VERSION 5.7 ;
BUSBITCHARS "[]" ;
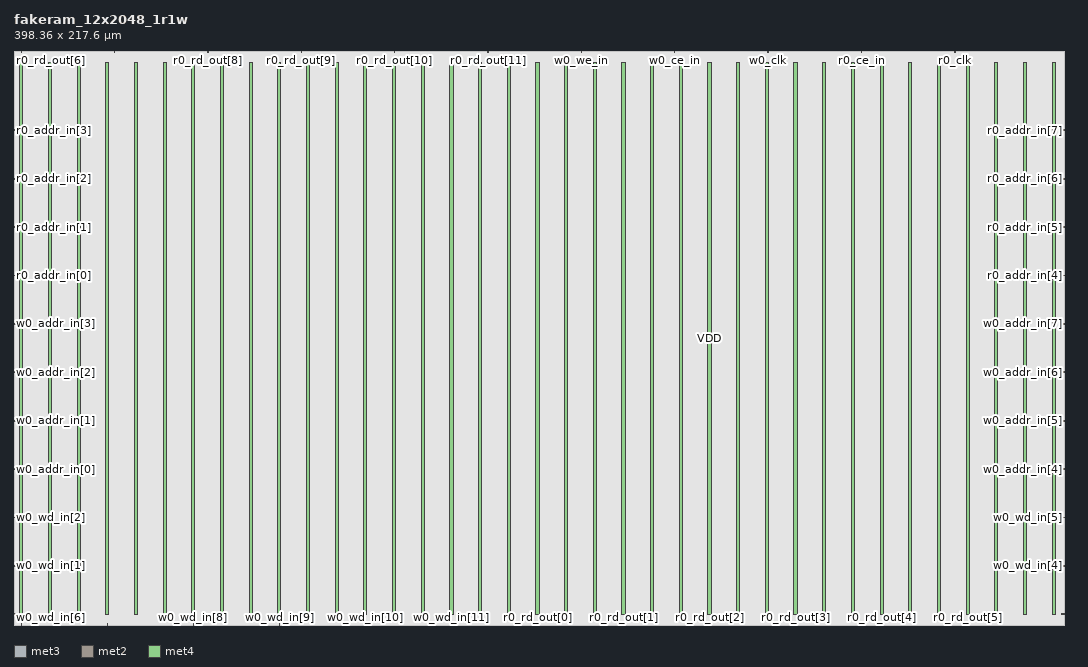
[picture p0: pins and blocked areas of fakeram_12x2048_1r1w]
MACRO fakeram_12x2048_1r1w
  FOREIGN fakeram_12x2048_1r1w 0 0 ;
  SYMMETRY X Y R90 ;
  SIZE 398.360 BY 217.600 ;
  CLASS BLOCK ;
  PIN w0_wd_in[0]
    DIRECTION INPUT ;
    USE SIGNAL ;
    SHAPE ABUTMENT ;
    PORT
      LAYER met3 ;
      RECT 0.000 3.930 0.900 4.230 ;
    END
  END w0_wd_in[0]
  PIN w0_wd_in[1]
    DIRECTION INPUT ;
    USE SIGNAL ;
    SHAPE ABUTMENT ;
    PORT
      LAYER met3 ;
      RECT 0.000 22.290 0.900 22.590 ;
    END
  END w0_wd_in[1]
  PIN w0_wd_in[2]
    DIRECTION INPUT ;
    USE SIGNAL ;
    SHAPE ABUTMENT ;
    PORT
      LAYER met3 ;
      RECT 0.000 40.650 0.900 40.950 ;
    END
  END w0_wd_in[2]
  PIN w0_wd_in[3]
    DIRECTION INPUT ;
    USE SIGNAL ;
    SHAPE ABUTMENT ;
    PORT
      LAYER met3 ;
      RECT 397.460 3.930 398.360 4.230 ;
    END
  END w0_wd_in[3]
  PIN w0_wd_in[4]
    DIRECTION INPUT ;
    USE SIGNAL ;
    SHAPE ABUTMENT ;
    PORT
      LAYER met3 ;
      RECT 397.460 22.290 398.360 22.590 ;
    END
  END w0_wd_in[4]
  PIN w0_wd_in[5]
    DIRECTION INPUT ;
    USE SIGNAL ;
    SHAPE ABUTMENT ;
    PORT
      LAYER met3 ;
      RECT 397.460 40.650 398.360 40.950 ;
    END
  END w0_wd_in[5]
  PIN w0_wd_in[6]
    DIRECTION INPUT ;
    USE SIGNAL ;
    SHAPE ABUTMENT ;
    PORT
      LAYER met2 ;
      RECT 2.690 0.000 2.830 0.420 ;
    END
  END w0_wd_in[6]
  PIN w0_wd_in[7]
    DIRECTION INPUT ;
    USE SIGNAL ;
    SHAPE ABUTMENT ;
    PORT
      LAYER met2 ;
      RECT 35.350 0.000 35.490 0.420 ;
    END
  END w0_wd_in[7]
  PIN w0_wd_in[8]
    DIRECTION INPUT ;
    USE SIGNAL ;
    SHAPE ABUTMENT ;
    PORT
      LAYER met2 ;
      RECT 68.010 0.000 68.150 0.420 ;
    END
  END w0_wd_in[8]
  PIN w0_wd_in[9]
    DIRECTION INPUT ;
    USE SIGNAL ;
    SHAPE ABUTMENT ;
    PORT
      LAYER met2 ;
      RECT 100.670 0.000 100.810 0.420 ;
    END
  END w0_wd_in[9]
  PIN w0_wd_in[10]
    DIRECTION INPUT ;
    USE SIGNAL ;
    SHAPE ABUTMENT ;
    PORT
      LAYER met2 ;
      RECT 133.330 0.000 133.470 0.420 ;
    END
  END w0_wd_in[10]
  PIN w0_wd_in[11]
    DIRECTION INPUT ;
    USE SIGNAL ;
    SHAPE ABUTMENT ;
    PORT
      LAYER met2 ;
      RECT 165.990 0.000 166.130 0.420 ;
    END
  END w0_wd_in[11]
  PIN r0_rd_out[0]
    DIRECTION OUTPUT ;
    USE SIGNAL ;
    SHAPE ABUTMENT ;
    PORT
      LAYER met2 ;
      RECT 198.650 0.000 198.790 0.420 ;
    END
  END r0_rd_out[0]
  PIN r0_rd_out[1]
    DIRECTION OUTPUT ;
    USE SIGNAL ;
    SHAPE ABUTMENT ;
    PORT
      LAYER met2 ;
      RECT 231.310 0.000 231.450 0.420 ;
    END
  END r0_rd_out[1]
  PIN r0_rd_out[2]
    DIRECTION OUTPUT ;
    USE SIGNAL ;
    SHAPE ABUTMENT ;
    PORT
      LAYER met2 ;
      RECT 263.970 0.000 264.110 0.420 ;
    END
  END r0_rd_out[2]
  PIN r0_rd_out[3]
    DIRECTION OUTPUT ;
    USE SIGNAL ;
    SHAPE ABUTMENT ;
    PORT
      LAYER met2 ;
      RECT 296.630 0.000 296.770 0.420 ;
    END
  END r0_rd_out[3]
  PIN r0_rd_out[4]
    DIRECTION OUTPUT ;
    USE SIGNAL ;
    SHAPE ABUTMENT ;
    PORT
      LAYER met2 ;
      RECT 329.290 0.000 329.430 0.420 ;
    END
  END r0_rd_out[4]
  PIN r0_rd_out[5]
    DIRECTION OUTPUT ;
    USE SIGNAL ;
    SHAPE ABUTMENT ;
    PORT
      LAYER met2 ;
      RECT 361.950 0.000 362.090 0.420 ;
    END
  END r0_rd_out[5]
  PIN r0_rd_out[6]
    DIRECTION OUTPUT ;
    USE SIGNAL ;
    SHAPE ABUTMENT ;
    PORT
      LAYER met2 ;
      RECT 2.690 217.180 2.830 217.600 ;
    END
  END r0_rd_out[6]
  PIN r0_rd_out[7]
    DIRECTION OUTPUT ;
    USE SIGNAL ;
    SHAPE ABUTMENT ;
    PORT
      LAYER met2 ;
      RECT 38.110 217.180 38.250 217.600 ;
    END
  END r0_rd_out[7]
  PIN r0_rd_out[8]
    DIRECTION OUTPUT ;
    USE SIGNAL ;
    SHAPE ABUTMENT ;
    PORT
      LAYER met2 ;
      RECT 73.530 217.180 73.670 217.600 ;
    END
  END r0_rd_out[8]
  PIN r0_rd_out[9]
    DIRECTION OUTPUT ;
    USE SIGNAL ;
    SHAPE ABUTMENT ;
    PORT
      LAYER met2 ;
      RECT 108.950 217.180 109.090 217.600 ;
    END
  END r0_rd_out[9]
  PIN r0_rd_out[10]
    DIRECTION OUTPUT ;
    USE SIGNAL ;
    SHAPE ABUTMENT ;
    PORT
      LAYER met2 ;
      RECT 144.370 217.180 144.510 217.600 ;
    END
  END r0_rd_out[10]
  PIN r0_rd_out[11]
    DIRECTION OUTPUT ;
    USE SIGNAL ;
    SHAPE ABUTMENT ;
    PORT
      LAYER met2 ;
      RECT 179.790 217.180 179.930 217.600 ;
    END
  END r0_rd_out[11]
  PIN w0_addr_in[0]
    DIRECTION INPUT ;
    USE SIGNAL ;
    SHAPE ABUTMENT ;
    PORT
      LAYER met3 ;
      RECT 0.000 59.010 0.900 59.310 ;
    END
  END w0_addr_in[0]
  PIN w0_addr_in[1]
    DIRECTION INPUT ;
    USE SIGNAL ;
    SHAPE ABUTMENT ;
    PORT
      LAYER met3 ;
      RECT 0.000 77.370 0.900 77.670 ;
    END
  END w0_addr_in[1]
  PIN w0_addr_in[2]
    DIRECTION INPUT ;
    USE SIGNAL ;
    SHAPE ABUTMENT ;
    PORT
      LAYER met3 ;
      RECT 0.000 95.730 0.900 96.030 ;
    END
  END w0_addr_in[2]
  PIN w0_addr_in[3]
    DIRECTION INPUT ;
    USE SIGNAL ;
    SHAPE ABUTMENT ;
    PORT
      LAYER met3 ;
      RECT 0.000 114.090 0.900 114.390 ;
    END
  END w0_addr_in[3]
  PIN w0_addr_in[4]
    DIRECTION INPUT ;
    USE SIGNAL ;
    SHAPE ABUTMENT ;
    PORT
      LAYER met3 ;
      RECT 397.460 59.010 398.360 59.310 ;
    END
  END w0_addr_in[4]
  PIN w0_addr_in[5]
    DIRECTION INPUT ;
    USE SIGNAL ;
    SHAPE ABUTMENT ;
    PORT
      LAYER met3 ;
      RECT 397.460 77.370 398.360 77.670 ;
    END
  END w0_addr_in[5]
  PIN w0_addr_in[6]
    DIRECTION INPUT ;
    USE SIGNAL ;
    SHAPE ABUTMENT ;
    PORT
      LAYER met3 ;
      RECT 397.460 95.730 398.360 96.030 ;
    END
  END w0_addr_in[6]
  PIN w0_addr_in[7]
    DIRECTION INPUT ;
    USE SIGNAL ;
    SHAPE ABUTMENT ;
    PORT
      LAYER met3 ;
      RECT 397.460 114.090 398.360 114.390 ;
    END
  END w0_addr_in[7]
  PIN r0_addr_in[0]
    DIRECTION INPUT ;
    USE SIGNAL ;
    SHAPE ABUTMENT ;
    PORT
      LAYER met3 ;
      RECT 0.000 132.450 0.900 132.750 ;
    END
  END r0_addr_in[0]
  PIN r0_addr_in[1]
    DIRECTION INPUT ;
    USE SIGNAL ;
    SHAPE ABUTMENT ;
    PORT
      LAYER met3 ;
      RECT 0.000 150.810 0.900 151.110 ;
    END
  END r0_addr_in[1]
  PIN r0_addr_in[2]
    DIRECTION INPUT ;
    USE SIGNAL ;
    SHAPE ABUTMENT ;
    PORT
      LAYER met3 ;
      RECT 0.000 169.170 0.900 169.470 ;
    END
  END r0_addr_in[2]
  PIN r0_addr_in[3]
    DIRECTION INPUT ;
    USE SIGNAL ;
    SHAPE ABUTMENT ;
    PORT
      LAYER met3 ;
      RECT 0.000 187.530 0.900 187.830 ;
    END
  END r0_addr_in[3]
  PIN r0_addr_in[4]
    DIRECTION INPUT ;
    USE SIGNAL ;
    SHAPE ABUTMENT ;
    PORT
      LAYER met3 ;
      RECT 397.460 132.450 398.360 132.750 ;
    END
  END r0_addr_in[4]
  PIN r0_addr_in[5]
    DIRECTION INPUT ;
    USE SIGNAL ;
    SHAPE ABUTMENT ;
    PORT
      LAYER met3 ;
      RECT 397.460 150.810 398.360 151.110 ;
    END
  END r0_addr_in[5]
  PIN r0_addr_in[6]
    DIRECTION INPUT ;
    USE SIGNAL ;
    SHAPE ABUTMENT ;
    PORT
      LAYER met3 ;
      RECT 397.460 169.170 398.360 169.470 ;
    END
  END r0_addr_in[6]
  PIN r0_addr_in[7]
    DIRECTION INPUT ;
    USE SIGNAL ;
    SHAPE ABUTMENT ;
    PORT
      LAYER met3 ;
      RECT 397.460 187.530 398.360 187.830 ;
    END
  END r0_addr_in[7]
  PIN w0_we_in
    DIRECTION INPUT ;
    USE SIGNAL ;
    SHAPE ABUTMENT ;
    PORT
      LAYER met2 ;
      RECT 215.210 217.180 215.350 217.600 ;
    END
  END w0_we_in
  PIN w0_ce_in
    DIRECTION INPUT ;
    USE SIGNAL ;
    SHAPE ABUTMENT ;
    PORT
      LAYER met2 ;
      RECT 250.630 217.180 250.770 217.600 ;
    END
  END w0_ce_in
  PIN w0_clk
    DIRECTION INPUT ;
    USE SIGNAL ;
    SHAPE ABUTMENT ;
    PORT
      LAYER met2 ;
      RECT 286.050 217.180 286.190 217.600 ;
    END
  END w0_clk
  PIN r0_ce_in
    DIRECTION INPUT ;
    USE SIGNAL ;
    SHAPE ABUTMENT ;
    PORT
      LAYER met2 ;
      RECT 321.470 217.180 321.610 217.600 ;
    END
  END r0_ce_in
  PIN r0_clk
    DIRECTION INPUT ;
    USE SIGNAL ;
    SHAPE ABUTMENT ;
    PORT
      LAYER met2 ;
      RECT 356.890 217.180 357.030 217.600 ;
    END
  END r0_clk
  PIN VSS
    DIRECTION INOUT ;
    USE GROUND ;
    PORT
      LAYER met4 ;
      RECT 2.160 4.080 3.360 213.520 ;
      RECT 13.040 4.080 14.240 213.520 ;
      RECT 23.920 4.080 25.120 213.520 ;
      RECT 34.800 4.080 36.000 213.520 ;
      RECT 45.680 4.080 46.880 213.520 ;
      RECT 56.560 4.080 57.760 213.520 ;
      RECT 67.440 4.080 68.640 213.520 ;
      RECT 78.320 4.080 79.520 213.520 ;
      RECT 89.200 4.080 90.400 213.520 ;
      RECT 100.080 4.080 101.280 213.520 ;
      RECT 110.960 4.080 112.160 213.520 ;
      RECT 121.840 4.080 123.040 213.520 ;
      RECT 132.720 4.080 133.920 213.520 ;
      RECT 143.600 4.080 144.800 213.520 ;
      RECT 154.480 4.080 155.680 213.520 ;
      RECT 165.360 4.080 166.560 213.520 ;
      RECT 176.240 4.080 177.440 213.520 ;
      RECT 187.120 4.080 188.320 213.520 ;
      RECT 198.000 4.080 199.200 213.520 ;
      RECT 208.880 4.080 210.080 213.520 ;
      RECT 219.760 4.080 220.960 213.520 ;
      RECT 230.640 4.080 231.840 213.520 ;
      RECT 241.520 4.080 242.720 213.520 ;
      RECT 252.400 4.080 253.600 213.520 ;
      RECT 263.280 4.080 264.480 213.520 ;
      RECT 274.160 4.080 275.360 213.520 ;
      RECT 285.040 4.080 286.240 213.520 ;
      RECT 295.920 4.080 297.120 213.520 ;
      RECT 306.800 4.080 308.000 213.520 ;
      RECT 317.680 4.080 318.880 213.520 ;
      RECT 328.560 4.080 329.760 213.520 ;
      RECT 339.440 4.080 340.640 213.520 ;
      RECT 350.320 4.080 351.520 213.520 ;
      RECT 361.200 4.080 362.400 213.520 ;
      RECT 372.080 4.080 373.280 213.520 ;
      RECT 382.960 4.080 384.160 213.520 ;
      RECT 393.840 4.080 395.040 213.520 ;
    END
  END VSS
  PIN VDD
    DIRECTION INOUT ;
    USE POWER ;
    PORT
      LAYER met4 ;
      RECT 2.160 4.080 3.360 213.520 ;
      RECT 13.040 4.080 14.240 213.520 ;
      RECT 23.920 4.080 25.120 213.520 ;
      RECT 34.800 4.080 36.000 213.520 ;
      RECT 45.680 4.080 46.880 213.520 ;
      RECT 56.560 4.080 57.760 213.520 ;
      RECT 67.440 4.080 68.640 213.520 ;
      RECT 78.320 4.080 79.520 213.520 ;
      RECT 89.200 4.080 90.400 213.520 ;
      RECT 100.080 4.080 101.280 213.520 ;
      RECT 110.960 4.080 112.160 213.520 ;
      RECT 121.840 4.080 123.040 213.520 ;
      RECT 132.720 4.080 133.920 213.520 ;
      RECT 143.600 4.080 144.800 213.520 ;
      RECT 154.480 4.080 155.680 213.520 ;
      RECT 165.360 4.080 166.560 213.520 ;
      RECT 176.240 4.080 177.440 213.520 ;
      RECT 187.120 4.080 188.320 213.520 ;
      RECT 198.000 4.080 199.200 213.520 ;
      RECT 208.880 4.080 210.080 213.520 ;
      RECT 219.760 4.080 220.960 213.520 ;
      RECT 230.640 4.080 231.840 213.520 ;
      RECT 241.520 4.080 242.720 213.520 ;
      RECT 252.400 4.080 253.600 213.520 ;
      RECT 263.280 4.080 264.480 213.520 ;
      RECT 274.160 4.080 275.360 213.520 ;
      RECT 285.040 4.080 286.240 213.520 ;
      RECT 295.920 4.080 297.120 213.520 ;
      RECT 306.800 4.080 308.000 213.520 ;
      RECT 317.680 4.080 318.880 213.520 ;
      RECT 328.560 4.080 329.760 213.520 ;
      RECT 339.440 4.080 340.640 213.520 ;
      RECT 350.320 4.080 351.520 213.520 ;
      RECT 361.200 4.080 362.400 213.520 ;
      RECT 372.080 4.080 373.280 213.520 ;
      RECT 382.960 4.080 384.160 213.520 ;
      RECT 393.840 4.080 395.040 213.520 ;
    END
  END VDD
  OBS
    LAYER met1 ;
    RECT 0 0 398.360 217.600 ;
    LAYER met2 ;
    RECT 0 0 398.360 217.600 ;
    LAYER met3 ;
    RECT 0 0 398.360 217.600 ;
    LAYER met4 ;
    RECT 0 0 398.360 217.600 ;
  END
END fakeram_12x2048_1r1w

END LIBRARY
